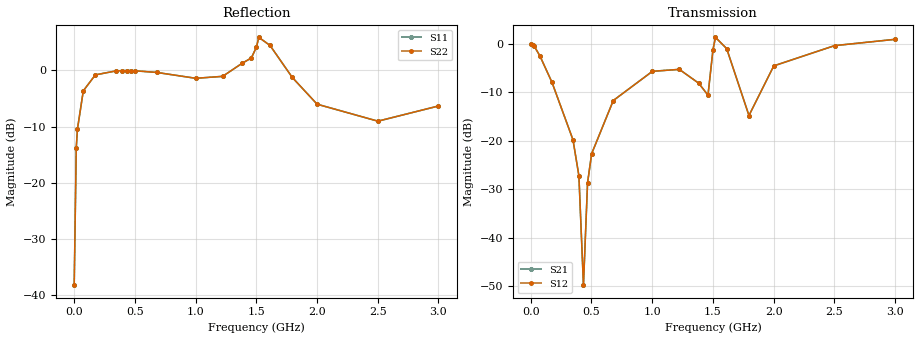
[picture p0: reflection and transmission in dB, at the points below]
!s-Parameter Generated by FASTRON Sdn. Bhd.
!FASTRON P/N : MICC-R22X
!Keysight Technologies,E4991B,MY54100416,A.01.15
!Date: Fri Aug 21 15:56:42 2026
!Version  : Rev00 Fri Aug 21 15:56:42 2026
!Data & Calibration Information:
!PortZ  Port1:50+j0  Port2:50+j0
!When reading, reference impedance value at option line is always used.
!Remarks : This data is being provided solely for informational purposes.
!Freq	S11	S21	S12	S22
# Hz S dB R 50
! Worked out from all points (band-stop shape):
!   1601 points, 1 MHz to 3 GHz, reference 50 ohm
!   highest |S21| = 1.27 dB at 1.521 GHz (marker M1); lowest = -49.8 dB at 434 MHz (marker M2)
!   |S21| within 3 dB of the highest: 1.499 GHz to 1.623 GHz (124.5 MHz wide, 7.97 % of centre); 2.26 GHz to end of sweep (the widest 2 of 3)
!   lowest |S11| = -38.3 dB at 1 MHz (marker M3), VSWR 1.02, Z = 50.1 + j1.21 ohm
!   |S11| at or under -10 dB: start of sweep to 29.16 MHz
!   |S22| runs from -38.3 to 6.0 dB; largest |S21 - S12| = 0
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1000000  -38.30 82.4  -0.01 -0.7  -0.01 -0.7  -38.30 82.4
1.786938e7  -13.92 76.8  -0.23 -11.6  -0.23 -11.6  -13.92 76.8
2.724125e7  -10.53 71.4  -0.47 -17.3  -0.47 -17.3  -10.53 71.4
7.5975e7  -3.63 48.0  -2.58 -41.2  -2.58 -41.2  -3.63 48.0
1.753169e8  -0.79 23.4  -8.02 -65.9  -8.02 -65.9  -0.79 23.4
3.477594e8  -0.07 5.8  -19.84 -82.3  -19.84 -82.3  -0.07 5.8
3.964931e8  -0.04 2.5  -27.25 -83.2  -27.25 -83.2  -0.04 2.5
4.339806e8  -0.03 0.0  -49.78 -9.6  -49.78 -9.6  -0.03 0.0
4.677194e8  -0.04 -2.1  -28.69 82.6  -28.69 82.6  -0.04 -2.1
5.014581e8  -0.06 -4.2  -22.70 82.9  -22.70 82.9  -0.06 -4.2
6.795238e8  -0.35 -15.0  -11.74 73.8  -11.74 73.8  -0.35 -15.0
1.001916e9  -1.40 -31.2  -5.72 58.3  -5.72 58.3  -1.40 -31.2
1.223092e9  -1.05 -32.7  -5.32 62.0  -5.32 62.0  -1.05 -32.7
1.382414e9  1.26 -19.2  -8.16 103.6  -8.16 103.6  1.26 -19.2
1.459264e9  2.23 1.4  -10.64 -173.8  -10.64 -173.8  2.23 1.4
1.5005e9  4.11 28.3  -1.24 -118.5  -1.24 -118.5  4.11 28.3
1.521118e9  5.90 25.9  1.27 -132.0  1.27 -132.0  5.90 25.9
1.612962e9  4.47 25.8  -1.04 -124.8  -1.04 -124.8  4.47 25.8
1.796651e9  -1.25 7.6  -14.83 -38.9  -14.83 -38.9  -1.25 7.6
2.000958e9  -6.02 -25.4  -4.60 21.4  -4.60 21.4  -6.02 -25.4
2.501416e9  -9.05 -72.0  -0.43 20.6  -0.43 20.6  -9.05 -72.0
3e9  -6.34 -89.4  0.87 25.8  0.87 25.8  -6.34 -89.4
